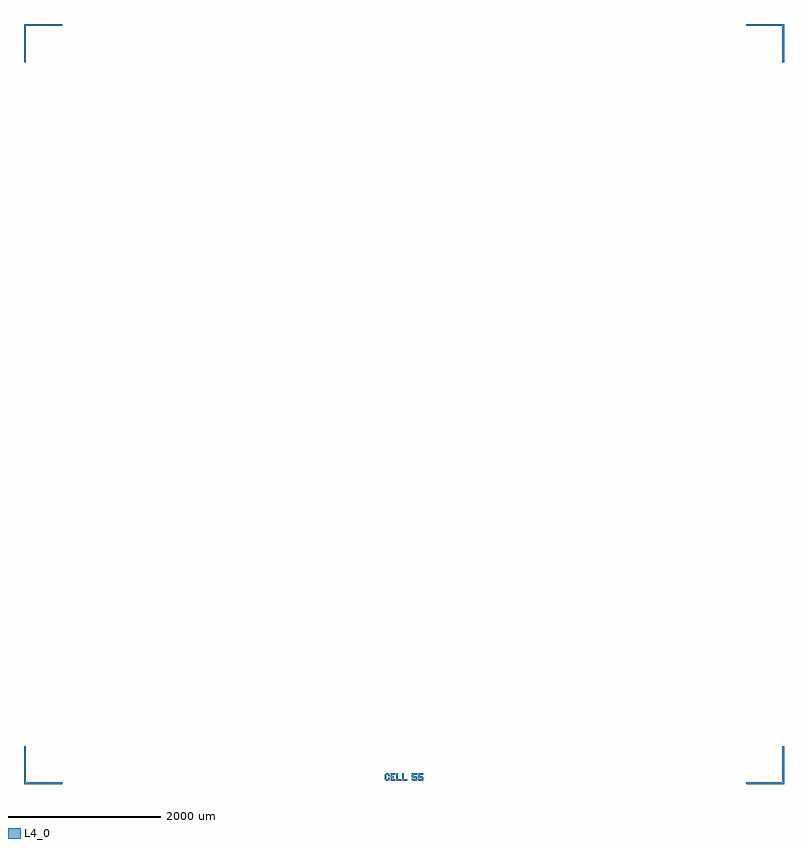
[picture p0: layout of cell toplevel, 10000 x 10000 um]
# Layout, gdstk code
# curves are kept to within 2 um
import gdstk
lib = gdstk.Library(unit=1e-6, precision=1e-09)
def P(c, l, *ps):  # polygons
    for p in ps: c.add(gdstk.Polygon(p, *l))
L4_0 = (4, 0)

toplevel = lib.new_cell('toplevel')
P(toplevel, L4_0, [(5000,5000),(5000,4500),(4980,4500),(4980,4980),(4500,4980),(4500,5000)],
  [(-5000,5000),(-5000,4500),(-4980,4500),(-4980,4980),(-4500,4980),(-4500,5000)],
  [(5000,-5000),(5000,-4500),(4980,-4500),(4980,-4980),(4500,-4980),(4500,-5000)],
  [(-5000,-5000),(-5000,-4500),(-4980,-4500),(-4980,-4980),(-4500,-4980),(-4500,-5000)],
  [(-235,-4960),(-255,-4940),(-255,-4880),(-235,-4860),(-205,-4860),(-185,-4880),(-185,-4900),(-205,-4900),(-205,-4890),(-215,-4880),(-225,-4880),(-235,-4890),(-235,-4930),(-225,-4940),(-215,-4940),(-205,-4930),(-205,-4920),(-185,-4920),(-185,-4940),(-205,-4960)],
  [(-115,-4860),(-115,-4880),(-155,-4880),(-155,-4900),(-135,-4900),(-135,-4920),(-155,-4920),(-155,-4940),(-115,-4940),(-115,-4960),(-175,-4960),(-175,-4860),(-115,-4860)],
  [(-105,-4860),(-85,-4860),(-85,-4940),(-35,-4940),(-35,-4960),(-105,-4960),(-105,-4860)],
  [(-25,-4860),(-5,-4860),(-5,-4940),(45,-4940),(45,-4960),(-25,-4960),(-25,-4860)],
  [(175,-4880),(125,-4880),(125,-4900),(165,-4900),(175,-4910),(175,-4950),(165,-4960),(115,-4960),(105,-4950),(105,-4930),(125,-4930),(125,-4940),(155,-4940),(155,-4920),(115,-4920),(105,-4910),(105,-4860),(175,-4860)],
  [(255,-4880),(205,-4880),(205,-4900),(245,-4900),(255,-4910),(255,-4950),(245,-4960),(195,-4960),(185,-4950),(185,-4930),(205,-4930),(205,-4940),(235,-4940),(235,-4920),(195,-4920),(185,-4910),(185,-4860),(255,-4860)])

lib.write_gds('toplevel.gds')
